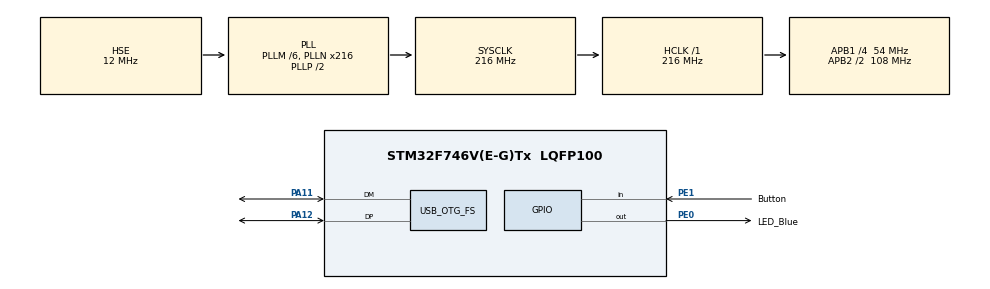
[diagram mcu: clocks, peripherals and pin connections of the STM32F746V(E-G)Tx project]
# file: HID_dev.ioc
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Dma.MEMTOMEM.0.Direction=DMA_MEMORY_TO_MEMORY
Dma.MEMTOMEM.0.FIFOMode=DMA_FIFOMODE_ENABLE
Dma.MEMTOMEM.0.FIFOThreshold=DMA_FIFO_THRESHOLD_FULL
Dma.MEMTOMEM.0.Instance=DMA2_Stream0
Dma.MEMTOMEM.0.MemBurst=DMA_MBURST_SINGLE
Dma.MEMTOMEM.0.MemDataAlignment=DMA_MDATAALIGN_BYTE
Dma.MEMTOMEM.0.MemInc=DMA_MINC_ENABLE
Dma.MEMTOMEM.0.Mode=DMA_NORMAL
Dma.MEMTOMEM.0.PeriphBurst=DMA_PBURST_SINGLE
Dma.MEMTOMEM.0.PeriphDataAlignment=DMA_PDATAALIGN_BYTE
Dma.MEMTOMEM.0.PeriphInc=DMA_PINC_ENABLE
Dma.MEMTOMEM.0.Priority=DMA_PRIORITY_LOW
Dma.Request0=MEMTOMEM
FREERTOS.Tasks01=defaultTask,0,128,StartDefaultTask,Default,NULL
FREERTOS.configUSE_PREEMPTION=0
Mcu.Family=STM32F7
Mcu.Name=STM32F746V(E-G)Tx
Mcu.Package=LQFP100
NVIC.OTG_FS_IRQn=true\:5\:0\:false\:false\:true\:true
NVIC.PriorityGroup=NVIC_PRIORITYGROUP_4
PA11.Mode=Device_Only
PA11.Signal=USB_OTG_FS_DM
PA12.Mode=Device_Only
PA12.Signal=USB_OTG_FS_DP
PE0.GPIO_Label=LED_Blue
PE0.Signal=GPIO_Output
PE1.GPIO_Label=Button
PE1.Signal=GPIO_Input
PH0/OSC_IN.Mode=HSE-External-Oscillator
PH0/OSC_IN.Signal=RCC_OSC_IN
PH1/OSC_OUT.Mode=HSE-External-Oscillator
PH1/OSC_OUT.Signal=RCC_OSC_OUT
ProjectManager.HeapSize=0x200
ProjectManager.StackSize=0x400
ProjectManager.TargetToolchain=SW4STM32
RCC.AHBFreq_Value=216000000
RCC.APB1CLKDivider=RCC_HCLK_DIV4
RCC.APB1Freq_Value=54000000
RCC.APB1TimFreq_Value=108000000
RCC.APB2CLKDivider=RCC_HCLK_DIV2
RCC.APB2Freq_Value=108000000
RCC.APB2TimFreq_Value=216000000
RCC.CortexFreq_Value=216000000
RCC.HCLKFreq_Value=216000000
RCC.HSE_VALUE=12000000
RCC.HSI_VALUE=16000000
RCC.LSE_VALUE=32768
RCC.PLLM=12
RCC.PLLN=432
RCC.PLLQ=9
RCC.SYSCLKFreq_VALUE=216000000
RCC.SYSCLKSource=RCC_SYSCLKSOURCE_PLLCLK
RCC.USBFreq_Value=48000000
RCC.VCOOutputFreq_Value=432000000
USB_OTG_FS.VirtualMode=Device_Only
USB_OTG_FS.vbus_sensing_enable=DISABLE
VP_FREERTOS_VS_ENABLE.Mode=Enabled
board=HID_dev

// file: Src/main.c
/**
  ******************************************************************************
  * File Name          : main.c
  * Description        : Main program body
  ******************************************************************************
  * This notice applies to any and all portions of this file
  * that are not between comment pairs USER CODE BEGIN and
  * USER CODE END. Other portions of this file, whether
  * inserted by the user or by software development tools
  * are owned by their respective copyright owners.
  *
  * Copyright (c) 2017 STMicroelectronics International N.V.
  * All rights reserved.
  *
  * Redistribution and use in source and binary forms, with or without
  * modification, are permitted, provided that the following conditions are met:
  *
  * 1. Redistribution of source code must retain the above copyright notice,
  *    this list of conditions and the following disclaimer.
  * 2. Redistributions in binary form must reproduce the above copyright notice,
  *    this list of conditions and the following disclaimer in the documentation
  *    and/or other materials provided with the distribution.
  * 3. Neither the name of STMicroelectronics nor the names of other
  *    contributors to this software may be used to endorse or promote products
  *    derived from this software without specific written permission.
  * 4. This software, including modifications and/or derivative works of this
  *    software, must execute solely and exclusively on microcontroller or
  *    microprocessor devices manufactured by or for STMicroelectronics.
  * 5. Redistribution and use of this software other than as permitted under
  *    this license is void and will automatically terminate your rights under
  *    this license.
  *
  * THIS SOFTWARE IS PROVIDED BY STMICROELECTRONICS AND CONTRIBUTORS "AS IS"
  * AND ANY EXPRESS, IMPLIED OR STATUTORY WARRANTIES, INCLUDING, BUT NOT
  * LIMITED TO, THE IMPLIED WARRANTIES OF MERCHANTABILITY, FITNESS FOR A
  * PARTICULAR PURPOSE AND NON-INFRINGEMENT OF THIRD PARTY INTELLECTUAL PROPERTY
  * RIGHTS ARE DISCLAIMED TO THE FULLEST EXTENT PERMITTED BY LAW. IN NO EVENT
  * SHALL STMICROELECTRONICS OR CONTRIBUTORS BE LIABLE FOR ANY DIRECT, INDIRECT,
  * INCIDENTAL, SPECIAL, EXEMPLARY, OR CONSEQUENTIAL DAMAGES (INCLUDING, BUT NOT
  * LIMITED TO, PROCUREMENT OF SUBSTITUTE GOODS OR SERVICES; LOSS OF USE, DATA,
  * OR PROFITS; OR BUSINESS INTERRUPTION) HOWEVER CAUSED AND ON ANY THEORY OF
  * LIABILITY, WHETHER IN CONTRACT, STRICT LIABILITY, OR TORT (INCLUDING
  * NEGLIGENCE OR OTHERWISE) ARISING IN ANY WAY OUT OF THE USE OF THIS SOFTWARE,
  * EVEN IF ADVISED OF THE POSSIBILITY OF SUCH DAMAGE.
  *
  ******************************************************************************
  */
#include "main.h"
#include "stm32f7xx_hal.h"
#include "cmsis_os.h"

PCD_HandleTypeDef hpcd_USB_OTG_FS;

DMA_HandleTypeDef hdma_memtomem_dma2_stream0;
SRAM_HandleTypeDef hsram1;

osThreadId defaultTaskHandle;

/* USER CODE BEGIN PV */
/* Private variables ---------------------------------------------------------*/

/* USER CODE END PV */

void SystemClock_Config(void);
static void MX_GPIO_Init(void);
static void MX_DMA_Init(void);
static void MX_FMC_Init(void);
static void MX_USB_OTG_FS_PCD_Init(void);
void StartDefaultTask(void const * argument);

/* USER CODE BEGIN PFP */
/* Private function prototypes -----------------------------------------------*/

/* USER CODE END PFP */

/* USER CODE BEGIN 0 */
void mainThreadLauncher();
/* USER CODE END 0 */

int main(void)
{

  /* Enable I-Cache-------------------------------------------------------------*/
  SCB_EnableICache();

  /* Enable D-Cache-------------------------------------------------------------*/
  SCB_EnableDCache();

  /* MCU Configuration----------------------------------------------------------*/

  /* Reset of all peripherals, Initializes the Flash interface and the Systick. */
  HAL_Init();

  /* Configure the system clock */
  SystemClock_Config();

  /* Initialize all configured peripherals */
  MX_GPIO_Init();
  MX_DMA_Init();
  MX_FMC_Init();
  MX_USB_OTG_FS_PCD_Init();

  /* Create the thread(s) */
  /* definition and creation of defaultTask */
  osThreadDef(defaultTask, StartDefaultTask, osPriorityNormal, 0, 128);
  defaultTaskHandle = osThreadCreate(osThread(defaultTask), NULL);

  /* Start scheduler */
  osKernelStart();

  /* We should never get here as control is now taken by the scheduler */

  /* Infinite loop */
  while (1)
  {

  }

}

/** System Clock Configuration
*/
void SystemClock_Config(void)
{

  RCC_OscInitTypeDef RCC_OscInitStruct;
  RCC_ClkInitTypeDef RCC_ClkInitStruct;
  RCC_PeriphCLKInitTypeDef PeriphClkInitStruct;

    /**Configure the main internal regulator output voltage
    */
  __HAL_RCC_PWR_CLK_ENABLE();

  __HAL_PWR_VOLTAGESCALING_CONFIG(PWR_REGULATOR_VOLTAGE_SCALE1);

    /**Initializes the CPU, AHB and APB busses clocks
    */
  RCC_OscInitStruct.OscillatorType = RCC_OSCILLATORTYPE_HSE;
  RCC_OscInitStruct.HSEState = RCC_HSE_ON;
  RCC_OscInitStruct.PLL.PLLState = RCC_PLL_ON;
  RCC_OscInitStruct.PLL.PLLSource = RCC_PLLSOURCE_HSE;
  RCC_OscInitStruct.PLL.PLLM = 6;
  RCC_OscInitStruct.PLL.PLLN = 216;
  RCC_OscInitStruct.PLL.PLLP = RCC_PLLP_DIV2;
  RCC_OscInitStruct.PLL.PLLQ = 9;
  if (HAL_RCC_OscConfig(&RCC_OscInitStruct) != HAL_OK)
  {
    _Error_Handler(__FILE__, __LINE__);
  }

    /**Activate the Over-Drive mode
    */
  if (HAL_PWREx_EnableOverDrive() != HAL_OK)
  {
    _Error_Handler(__FILE__, __LINE__);
  }

    /**Initializes the CPU, AHB and APB busses clocks
    */
  RCC_ClkInitStruct.ClockType = RCC_CLOCKTYPE_HCLK|RCC_CLOCKTYPE_SYSCLK
                              |RCC_CLOCKTYPE_PCLK1|RCC_CLOCKTYPE_PCLK2;
  RCC_ClkInitStruct.SYSCLKSource = RCC_SYSCLKSOURCE_PLLCLK;
  RCC_ClkInitStruct.AHBCLKDivider = RCC_SYSCLK_DIV1;
  RCC_ClkInitStruct.APB1CLKDivider = RCC_HCLK_DIV4;
  RCC_ClkInitStruct.APB2CLKDivider = RCC_HCLK_DIV2;

  if (HAL_RCC_ClockConfig(&RCC_ClkInitStruct, FLASH_LATENCY_7) != HAL_OK)
  {
    _Error_Handler(__FILE__, __LINE__);
  }

  PeriphClkInitStruct.PeriphClockSelection = RCC_PERIPHCLK_CLK48;
  PeriphClkInitStruct.Clk48ClockSelection = RCC_CLK48SOURCE_PLL;
  if (HAL_RCCEx_PeriphCLKConfig(&PeriphClkInitStruct) != HAL_OK)
  {
    _Error_Handler(__FILE__, __LINE__);
  }

    /**Configure the Systick interrupt time
    */
  HAL_SYSTICK_Config(HAL_RCC_GetHCLKFreq()/1000);

    /**Configure the Systick
    */
  HAL_SYSTICK_CLKSourceConfig(SYSTICK_CLKSOURCE_HCLK);

  /* SysTick_IRQn interrupt configuration */
  HAL_NVIC_SetPriority(SysTick_IRQn, 15, 0);
}

/* USB_OTG_FS init function */
static void MX_USB_OTG_FS_PCD_Init(void)
{

  hpcd_USB_OTG_FS.Instance = USB_OTG_FS;
  hpcd_USB_OTG_FS.Init.dev_endpoints = 6;
  hpcd_USB_OTG_FS.Init.speed = PCD_SPEED_FULL;
  hpcd_USB_OTG_FS.Init.dma_enable = DISABLE;
  hpcd_USB_OTG_FS.Init.ep0_mps = DEP0CTL_MPS_64;
  hpcd_USB_OTG_FS.Init.phy_itface = PCD_PHY_EMBEDDED;
  hpcd_USB_OTG_FS.Init.Sof_enable = DISABLE;
  hpcd_USB_OTG_FS.Init.low_power_enable = DISABLE;
  hpcd_USB_OTG_FS.Init.lpm_enable = DISABLE;
  hpcd_USB_OTG_FS.Init.vbus_sensing_enable = DISABLE;
  hpcd_USB_OTG_FS.Init.use_dedicated_ep1 = DISABLE;
  if (HAL_PCD_Init(&hpcd_USB_OTG_FS) != HAL_OK)
  {
    _Error_Handler(__FILE__, __LINE__);
  }

}

static void MX_DMA_Init(void)
{
  /* DMA controller clock enable */
  __HAL_RCC_DMA2_CLK_ENABLE();

  /* Configure DMA request hdma_memtomem_dma2_stream0 on DMA2_Stream0 */
  hdma_memtomem_dma2_stream0.Instance = DMA2_Stream0;
  hdma_memtomem_dma2_stream0.Init.Channel = DMA_CHANNEL_0;
  hdma_memtomem_dma2_stream0.Init.Direction = DMA_MEMORY_TO_MEMORY;
  hdma_memtomem_dma2_stream0.Init.PeriphInc = DMA_PINC_ENABLE;
  hdma_memtomem_dma2_stream0.Init.MemInc = DMA_MINC_DISABLE;
  hdma_memtomem_dma2_stream0.Init.PeriphDataAlignment = DMA_PDATAALIGN_WORD;
  hdma_memtomem_dma2_stream0.Init.MemDataAlignment = DMA_MDATAALIGN_WORD;
  hdma_memtomem_dma2_stream0.Init.Mode = DMA_NORMAL;
  hdma_memtomem_dma2_stream0.Init.Priority = DMA_PRIORITY_VERY_HIGH;
  hdma_memtomem_dma2_stream0.Init.FIFOMode = DMA_FIFOMODE_ENABLE;
  hdma_memtomem_dma2_stream0.Init.FIFOThreshold = DMA_FIFO_THRESHOLD_FULL;
  hdma_memtomem_dma2_stream0.Init.MemBurst = DMA_MBURST_SINGLE;
  hdma_memtomem_dma2_stream0.Init.PeriphBurst = DMA_PBURST_SINGLE;
  if (HAL_DMA_Init(&hdma_memtomem_dma2_stream0) != HAL_OK)
  {
    _Error_Handler(__FILE__, __LINE__);
  }

  /* DMA interrupt init */
  /* DMA2_Stream0_IRQn interrupt configuration */
  HAL_NVIC_SetPriority(DMA2_Stream0_IRQn, 5, 0);
  HAL_NVIC_EnableIRQ(DMA2_Stream0_IRQn);

}
/* FMC initialization function */
static void MX_FMC_Init(void)
{
  FMC_NORSRAM_TimingTypeDef Timing;

  /** Perform the SRAM1 memory initialization sequence
  */
  hsram1.Instance = FMC_NORSRAM_DEVICE;
  hsram1.Extended = FMC_NORSRAM_EXTENDED_DEVICE;
  /* hsram1.Init */
  hsram1.Init.NSBank = FMC_NORSRAM_BANK1;
  hsram1.Init.DataAddressMux = FMC_DATA_ADDRESS_MUX_DISABLE;
  hsram1.Init.MemoryType = FMC_MEMORY_TYPE_SRAM;
  hsram1.Init.MemoryDataWidth = FMC_NORSRAM_MEM_BUS_WIDTH_16;
  hsram1.Init.BurstAccessMode = FMC_BURST_ACCESS_MODE_DISABLE;
  hsram1.Init.WaitSignalPolarity = FMC_WAIT_SIGNAL_POLARITY_LOW;
  hsram1.Init.WaitSignalActive = FMC_WAIT_TIMING_BEFORE_WS;
  hsram1.Init.WriteOperation = FMC_WRITE_OPERATION_ENABLE;
  hsram1.Init.WaitSignal = FMC_WAIT_SIGNAL_DISABLE;
  hsram1.Init.ExtendedMode = FMC_EXTENDED_MODE_DISABLE;
  hsram1.Init.AsynchronousWait = FMC_ASYNCHRONOUS_WAIT_DISABLE;
  hsram1.Init.WriteBurst = FMC_WRITE_BURST_DISABLE;
  hsram1.Init.ContinuousClock = FMC_CONTINUOUS_CLOCK_SYNC_ONLY;
  hsram1.Init.WriteFifo = FMC_WRITE_FIFO_ENABLE;
  hsram1.Init.PageSize = FMC_PAGE_SIZE_NONE;
  /* Timing */
  Timing.AddressSetupTime = 15;
  Timing.AddressHoldTime = 15;
  Timing.DataSetupTime = 255;
  Timing.BusTurnAroundDuration = 15;
  Timing.CLKDivision = 16;
  Timing.DataLatency = 17;
  Timing.AccessMode = FMC_ACCESS_MODE_A;
  /* ExtTiming */

  if (HAL_SRAM_Init(&hsram1, &Timing, NULL) != HAL_OK)
  {
    _Error_Handler(__FILE__, __LINE__);
  }

}

/** Configure pins as
        * Analog
        * Input
        * Output
        * EVENT_OUT
        * EXTI
*/
static void MX_GPIO_Init(void)
{

  GPIO_InitTypeDef GPIO_InitStruct;

  /* GPIO Ports Clock Enable */
  __HAL_RCC_GPIOH_CLK_ENABLE();
  __HAL_RCC_GPIOE_CLK_ENABLE();
  __HAL_RCC_GPIOD_CLK_ENABLE();
  __HAL_RCC_GPIOC_CLK_ENABLE();
  __HAL_RCC_GPIOA_CLK_ENABLE();

  /*Configure GPIO pin Output Level */
  HAL_GPIO_WritePin(LCD_RESET_GPIO_Port, LCD_RESET_Pin, GPIO_PIN_RESET);

  /*Configure GPIO pin Output Level */
  HAL_GPIO_WritePin(LED_GPIO_Port, LED_Pin, GPIO_PIN_RESET);

  /*Configure GPIO pin : LCD_RESET_Pin */
  GPIO_InitStruct.Pin = LCD_RESET_Pin;
  GPIO_InitStruct.Mode = GPIO_MODE_OUTPUT_PP;
  GPIO_InitStruct.Pull = GPIO_NOPULL;
  GPIO_InitStruct.Speed = GPIO_SPEED_FREQ_LOW;
  HAL_GPIO_Init(LCD_RESET_GPIO_Port, &GPIO_InitStruct);

  /*Configure GPIO pin : LED_Pin */
  GPIO_InitStruct.Pin = LED_Pin;
  GPIO_InitStruct.Mode = GPIO_MODE_OUTPUT_PP;
  GPIO_InitStruct.Pull = GPIO_NOPULL;
  GPIO_InitStruct.Speed = GPIO_SPEED_FREQ_LOW;
  HAL_GPIO_Init(LED_GPIO_Port, &GPIO_InitStruct);

}

/* StartDefaultTask function */
void StartDefaultTask(void const * argument)
{

  /* USER CODE BEGIN 5 */
	mainThreadLauncher();
  /* Infinite loop */
  for(;;)
  {
    osDelay(1);
  }
  /* USER CODE END 5 */
}

void _Error_Handler(char * file, int line)
{
  while(1)
  {
  }
}

/************************ (C) COPYRIGHT STMicroelectronics *****END OF FILE****/
